# Generated by innovus_enablement/scripts/gen_fakeram.py: abstract 64x124 SRAM.
# Geometry is an assumption (see script header), not PDK data.
VERSION 5.8 ;
BUSBITCHARS "[]" ;
DIVIDERCHAR "/" ;

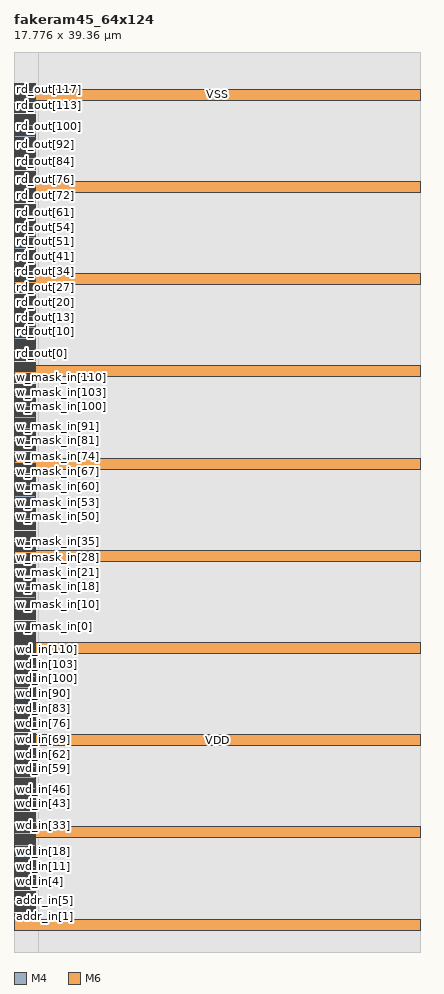
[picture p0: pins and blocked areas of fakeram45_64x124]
MACRO fakeram45_64x124
  CLASS BLOCK ;
  FOREIGN fakeram45_64x124 0 0 ;
  ORIGIN 0 0 ;
  SIZE 17.7760 BY 39.3600 ;
  SYMMETRY X Y R90 ;
  PIN clk
    DIRECTION INPUT ;
    USE CLOCK ;
    PORT
      LAYER M4 ;
        RECT 0 1.4640 0.9600 1.5120 ;
    END
  END clk
  PIN ce_in
    DIRECTION INPUT ;
    USE SIGNAL ;
    PORT
      LAYER M4 ;
        RECT 0 1.5600 0.9600 1.6080 ;
    END
  END ce_in
  PIN we_in
    DIRECTION INPUT ;
    USE SIGNAL ;
    PORT
      LAYER M4 ;
        RECT 0 1.6560 0.9600 1.7040 ;
    END
  END we_in
  PIN addr_in[0]
    DIRECTION INPUT ;
    USE SIGNAL ;
    PORT
      LAYER M4 ;
        RECT 0 1.7520 0.9600 1.8000 ;
    END
  END addr_in[0]
  PIN addr_in[1]
    DIRECTION INPUT ;
    USE SIGNAL ;
    PORT
      LAYER M4 ;
        RECT 0 1.8480 0.9600 1.8960 ;
    END
  END addr_in[1]
  PIN addr_in[2]
    DIRECTION INPUT ;
    USE SIGNAL ;
    PORT
      LAYER M4 ;
        RECT 0 1.9440 0.9600 1.9920 ;
    END
  END addr_in[2]
  PIN addr_in[3]
    DIRECTION INPUT ;
    USE SIGNAL ;
    PORT
      LAYER M4 ;
        RECT 0 2.0400 0.9600 2.0880 ;
    END
  END addr_in[3]
  PIN addr_in[4]
    DIRECTION INPUT ;
    USE SIGNAL ;
    PORT
      LAYER M4 ;
        RECT 0 2.1360 0.9600 2.1840 ;
    END
  END addr_in[4]
  PIN addr_in[5]
    DIRECTION INPUT ;
    USE SIGNAL ;
    PORT
      LAYER M4 ;
        RECT 0 2.2320 0.9600 2.2800 ;
    END
  END addr_in[5]
  PIN wd_in[0]
    DIRECTION INPUT ;
    USE SIGNAL ;
    PORT
      LAYER M4 ;
        RECT 0 2.3280 0.9600 2.3760 ;
    END
  END wd_in[0]
  PIN wd_in[1]
    DIRECTION INPUT ;
    USE SIGNAL ;
    PORT
      LAYER M4 ;
        RECT 0 2.4240 0.9600 2.4720 ;
    END
  END wd_in[1]
  PIN wd_in[2]
    DIRECTION INPUT ;
    USE SIGNAL ;
    PORT
      LAYER M4 ;
        RECT 0 2.5200 0.9600 2.5680 ;
    END
  END wd_in[2]
  PIN wd_in[3]
    DIRECTION INPUT ;
    USE SIGNAL ;
    PORT
      LAYER M4 ;
        RECT 0 2.6160 0.9600 2.6640 ;
    END
  END wd_in[3]
  PIN wd_in[4]
    DIRECTION INPUT ;
    USE SIGNAL ;
    PORT
      LAYER M4 ;
        RECT 0 2.7120 0.9600 2.7600 ;
    END
  END wd_in[4]
  PIN wd_in[5]
    DIRECTION INPUT ;
    USE SIGNAL ;
    PORT
      LAYER M4 ;
        RECT 0 2.8080 0.9600 2.8560 ;
    END
  END wd_in[5]
  PIN wd_in[6]
    DIRECTION INPUT ;
    USE SIGNAL ;
    PORT
      LAYER M4 ;
        RECT 0 2.9040 0.9600 2.9520 ;
    END
  END wd_in[6]
  PIN wd_in[7]
    DIRECTION INPUT ;
    USE SIGNAL ;
    PORT
      LAYER M4 ;
        RECT 0 3.0000 0.9600 3.0480 ;
    END
  END wd_in[7]
  PIN wd_in[8]
    DIRECTION INPUT ;
    USE SIGNAL ;
    PORT
      LAYER M4 ;
        RECT 0 3.0960 0.9600 3.1440 ;
    END
  END wd_in[8]
  PIN wd_in[9]
    DIRECTION INPUT ;
    USE SIGNAL ;
    PORT
      LAYER M4 ;
        RECT 0 3.1920 0.9600 3.2400 ;
    END
  END wd_in[9]
  PIN wd_in[10]
    DIRECTION INPUT ;
    USE SIGNAL ;
    PORT
      LAYER M4 ;
        RECT 0 3.2880 0.9600 3.3360 ;
    END
  END wd_in[10]
  PIN wd_in[11]
    DIRECTION INPUT ;
    USE SIGNAL ;
    PORT
      LAYER M4 ;
        RECT 0 3.3840 0.9600 3.4320 ;
    END
  END wd_in[11]
  PIN wd_in[12]
    DIRECTION INPUT ;
    USE SIGNAL ;
    PORT
      LAYER M4 ;
        RECT 0 3.4800 0.9600 3.5280 ;
    END
  END wd_in[12]
  PIN wd_in[13]
    DIRECTION INPUT ;
    USE SIGNAL ;
    PORT
      LAYER M4 ;
        RECT 0 3.5760 0.9600 3.6240 ;
    END
  END wd_in[13]
  PIN wd_in[14]
    DIRECTION INPUT ;
    USE SIGNAL ;
    PORT
      LAYER M4 ;
        RECT 0 3.6720 0.9600 3.7200 ;
    END
  END wd_in[14]
  PIN wd_in[15]
    DIRECTION INPUT ;
    USE SIGNAL ;
    PORT
      LAYER M4 ;
        RECT 0 3.7680 0.9600 3.8160 ;
    END
  END wd_in[15]
  PIN wd_in[16]
    DIRECTION INPUT ;
    USE SIGNAL ;
    PORT
      LAYER M4 ;
        RECT 0 3.8640 0.9600 3.9120 ;
    END
  END wd_in[16]
  PIN wd_in[17]
    DIRECTION INPUT ;
    USE SIGNAL ;
    PORT
      LAYER M4 ;
        RECT 0 3.9600 0.9600 4.0080 ;
    END
  END wd_in[17]
  PIN wd_in[18]
    DIRECTION INPUT ;
    USE SIGNAL ;
    PORT
      LAYER M4 ;
        RECT 0 4.0560 0.9600 4.1040 ;
    END
  END wd_in[18]
  PIN wd_in[19]
    DIRECTION INPUT ;
    USE SIGNAL ;
    PORT
      LAYER M4 ;
        RECT 0 4.1520 0.9600 4.2000 ;
    END
  END wd_in[19]
  PIN wd_in[20]
    DIRECTION INPUT ;
    USE SIGNAL ;
    PORT
      LAYER M4 ;
        RECT 0 4.2480 0.9600 4.2960 ;
    END
  END wd_in[20]
  PIN wd_in[21]
    DIRECTION INPUT ;
    USE SIGNAL ;
    PORT
      LAYER M4 ;
        RECT 0 4.3440 0.9600 4.3920 ;
    END
  END wd_in[21]
  PIN wd_in[22]
    DIRECTION INPUT ;
    USE SIGNAL ;
    PORT
      LAYER M4 ;
        RECT 0 4.4400 0.9600 4.4880 ;
    END
  END wd_in[22]
  PIN wd_in[23]
    DIRECTION INPUT ;
    USE SIGNAL ;
    PORT
      LAYER M4 ;
        RECT 0 4.5360 0.9600 4.5840 ;
    END
  END wd_in[23]
  PIN wd_in[24]
    DIRECTION INPUT ;
    USE SIGNAL ;
    PORT
      LAYER M4 ;
        RECT 0 4.6320 0.9600 4.6800 ;
    END
  END wd_in[24]
  PIN wd_in[25]
    DIRECTION INPUT ;
    USE SIGNAL ;
    PORT
      LAYER M4 ;
        RECT 0 4.7280 0.9600 4.7760 ;
    END
  END wd_in[25]
  PIN wd_in[26]
    DIRECTION INPUT ;
    USE SIGNAL ;
    PORT
      LAYER M4 ;
        RECT 0 4.8240 0.9600 4.8720 ;
    END
  END wd_in[26]
  PIN wd_in[27]
    DIRECTION INPUT ;
    USE SIGNAL ;
    PORT
      LAYER M4 ;
        RECT 0 4.9200 0.9600 4.9680 ;
    END
  END wd_in[27]
  PIN wd_in[28]
    DIRECTION INPUT ;
    USE SIGNAL ;
    PORT
      LAYER M4 ;
        RECT 0 5.0160 0.9600 5.0640 ;
    END
  END wd_in[28]
  PIN wd_in[29]
    DIRECTION INPUT ;
    USE SIGNAL ;
    PORT
      LAYER M4 ;
        RECT 0 5.1120 0.9600 5.1600 ;
    END
  END wd_in[29]
  PIN wd_in[30]
    DIRECTION INPUT ;
    USE SIGNAL ;
    PORT
      LAYER M4 ;
        RECT 0 5.2080 0.9600 5.2560 ;
    END
  END wd_in[30]
  PIN wd_in[31]
    DIRECTION INPUT ;
    USE SIGNAL ;
    PORT
      LAYER M4 ;
        RECT 0 5.3040 0.9600 5.3520 ;
    END
  END wd_in[31]
  PIN wd_in[32]
    DIRECTION INPUT ;
    USE SIGNAL ;
    PORT
      LAYER M4 ;
        RECT 0 5.4000 0.9600 5.4480 ;
    END
  END wd_in[32]
  PIN wd_in[33]
    DIRECTION INPUT ;
    USE SIGNAL ;
    PORT
      LAYER M4 ;
        RECT 0 5.4960 0.9600 5.5440 ;
    END
  END wd_in[33]
  PIN wd_in[34]
    DIRECTION INPUT ;
    USE SIGNAL ;
    PORT
      LAYER M4 ;
        RECT 0 5.5920 0.9600 5.6400 ;
    END
  END wd_in[34]
  PIN wd_in[35]
    DIRECTION INPUT ;
    USE SIGNAL ;
    PORT
      LAYER M4 ;
        RECT 0 5.6880 0.9600 5.7360 ;
    END
  END wd_in[35]
  PIN wd_in[36]
    DIRECTION INPUT ;
    USE SIGNAL ;
    PORT
      LAYER M4 ;
        RECT 0 5.7840 0.9600 5.8320 ;
    END
  END wd_in[36]
  PIN wd_in[37]
    DIRECTION INPUT ;
    USE SIGNAL ;
    PORT
      LAYER M4 ;
        RECT 0 5.8800 0.9600 5.9280 ;
    END
  END wd_in[37]
  PIN wd_in[38]
    DIRECTION INPUT ;
    USE SIGNAL ;
    PORT
      LAYER M4 ;
        RECT 0 5.9760 0.9600 6.0240 ;
    END
  END wd_in[38]
  PIN wd_in[39]
    DIRECTION INPUT ;
    USE SIGNAL ;
    PORT
      LAYER M4 ;
        RECT 0 6.0720 0.9600 6.1200 ;
    END
  END wd_in[39]
  PIN wd_in[40]
    DIRECTION INPUT ;
    USE SIGNAL ;
    PORT
      LAYER M4 ;
        RECT 0 6.1680 0.9600 6.2160 ;
    END
  END wd_in[40]
  PIN wd_in[41]
    DIRECTION INPUT ;
    USE SIGNAL ;
    PORT
      LAYER M4 ;
        RECT 0 6.2640 0.9600 6.3120 ;
    END
  END wd_in[41]
  PIN wd_in[42]
    DIRECTION INPUT ;
    USE SIGNAL ;
    PORT
      LAYER M4 ;
        RECT 0 6.3600 0.9600 6.4080 ;
    END
  END wd_in[42]
  PIN wd_in[43]
    DIRECTION INPUT ;
    USE SIGNAL ;
    PORT
      LAYER M4 ;
        RECT 0 6.4560 0.9600 6.5040 ;
    END
  END wd_in[43]
  PIN wd_in[44]
    DIRECTION INPUT ;
    USE SIGNAL ;
    PORT
      LAYER M4 ;
        RECT 0 6.5520 0.9600 6.6000 ;
    END
  END wd_in[44]
  PIN wd_in[45]
    DIRECTION INPUT ;
    USE SIGNAL ;
    PORT
      LAYER M4 ;
        RECT 0 6.6480 0.9600 6.6960 ;
    END
  END wd_in[45]
  PIN wd_in[46]
    DIRECTION INPUT ;
    USE SIGNAL ;
    PORT
      LAYER M4 ;
        RECT 0 6.7440 0.9600 6.7920 ;
    END
  END wd_in[46]
  PIN wd_in[47]
    DIRECTION INPUT ;
    USE SIGNAL ;
    PORT
      LAYER M4 ;
        RECT 0 6.8400 0.9600 6.8880 ;
    END
  END wd_in[47]
  PIN wd_in[48]
    DIRECTION INPUT ;
    USE SIGNAL ;
    PORT
      LAYER M4 ;
        RECT 0 6.9360 0.9600 6.9840 ;
    END
  END wd_in[48]
  PIN wd_in[49]
    DIRECTION INPUT ;
    USE SIGNAL ;
    PORT
      LAYER M4 ;
        RECT 0 7.0320 0.9600 7.0800 ;
    END
  END wd_in[49]
  PIN wd_in[50]
    DIRECTION INPUT ;
    USE SIGNAL ;
    PORT
      LAYER M4 ;
        RECT 0 7.1280 0.9600 7.1760 ;
    END
  END wd_in[50]
  PIN wd_in[51]
    DIRECTION INPUT ;
    USE SIGNAL ;
    PORT
      LAYER M4 ;
        RECT 0 7.2240 0.9600 7.2720 ;
    END
  END wd_in[51]
  PIN wd_in[52]
    DIRECTION INPUT ;
    USE SIGNAL ;
    PORT
      LAYER M4 ;
        RECT 0 7.3200 0.9600 7.3680 ;
    END
  END wd_in[52]
  PIN wd_in[53]
    DIRECTION INPUT ;
    USE SIGNAL ;
    PORT
      LAYER M4 ;
        RECT 0 7.4160 0.9600 7.4640 ;
    END
  END wd_in[53]
  PIN wd_in[54]
    DIRECTION INPUT ;
    USE SIGNAL ;
    PORT
      LAYER M4 ;
        RECT 0 7.5120 0.9600 7.5600 ;
    END
  END wd_in[54]
  PIN wd_in[55]
    DIRECTION INPUT ;
    USE SIGNAL ;
    PORT
      LAYER M4 ;
        RECT 0 7.6080 0.9600 7.6560 ;
    END
  END wd_in[55]
  PIN wd_in[56]
    DIRECTION INPUT ;
    USE SIGNAL ;
    PORT
      LAYER M4 ;
        RECT 0 7.7040 0.9600 7.7520 ;
    END
  END wd_in[56]
  PIN wd_in[57]
    DIRECTION INPUT ;
    USE SIGNAL ;
    PORT
      LAYER M4 ;
        RECT 0 7.8000 0.9600 7.8480 ;
    END
  END wd_in[57]
  PIN wd_in[58]
    DIRECTION INPUT ;
    USE SIGNAL ;
    PORT
      LAYER M4 ;
        RECT 0 7.8960 0.9600 7.9440 ;
    END
  END wd_in[58]
  PIN wd_in[59]
    DIRECTION INPUT ;
    USE SIGNAL ;
    PORT
      LAYER M4 ;
        RECT 0 7.9920 0.9600 8.0400 ;
    END
  END wd_in[59]
  PIN wd_in[60]
    DIRECTION INPUT ;
    USE SIGNAL ;
    PORT
      LAYER M4 ;
        RECT 0 8.0880 0.9600 8.1360 ;
    END
  END wd_in[60]
  PIN wd_in[61]
    DIRECTION INPUT ;
    USE SIGNAL ;
    PORT
      LAYER M4 ;
        RECT 0 8.1840 0.9600 8.2320 ;
    END
  END wd_in[61]
  PIN wd_in[62]
    DIRECTION INPUT ;
    USE SIGNAL ;
    PORT
      LAYER M4 ;
        RECT 0 8.2800 0.9600 8.3280 ;
    END
  END wd_in[62]
  PIN wd_in[63]
    DIRECTION INPUT ;
    USE SIGNAL ;
    PORT
      LAYER M4 ;
        RECT 0 8.3760 0.9600 8.4240 ;
    END
  END wd_in[63]
  PIN wd_in[64]
    DIRECTION INPUT ;
    USE SIGNAL ;
    PORT
      LAYER M4 ;
        RECT 0 8.4720 0.9600 8.5200 ;
    END
  END wd_in[64]
  PIN wd_in[65]
    DIRECTION INPUT ;
    USE SIGNAL ;
    PORT
      LAYER M4 ;
        RECT 0 8.5680 0.9600 8.6160 ;
    END
  END wd_in[65]
  PIN wd_in[66]
    DIRECTION INPUT ;
    USE SIGNAL ;
    PORT
      LAYER M4 ;
        RECT 0 8.6640 0.9600 8.7120 ;
    END
  END wd_in[66]
  PIN wd_in[67]
    DIRECTION INPUT ;
    USE SIGNAL ;
    PORT
      LAYER M4 ;
        RECT 0 8.7600 0.9600 8.8080 ;
    END
  END wd_in[67]
  PIN wd_in[68]
    DIRECTION INPUT ;
    USE SIGNAL ;
    PORT
      LAYER M4 ;
        RECT 0 8.8560 0.9600 8.9040 ;
    END
  END wd_in[68]
  PIN wd_in[69]
    DIRECTION INPUT ;
    USE SIGNAL ;
    PORT
      LAYER M4 ;
        RECT 0 8.9520 0.9600 9.0000 ;
    END
  END wd_in[69]
  PIN wd_in[70]
    DIRECTION INPUT ;
    USE SIGNAL ;
    PORT
      LAYER M4 ;
        RECT 0 9.0480 0.9600 9.0960 ;
    END
  END wd_in[70]
  PIN wd_in[71]
    DIRECTION INPUT ;
    USE SIGNAL ;
    PORT
      LAYER M4 ;
        RECT 0 9.1440 0.9600 9.1920 ;
    END
  END wd_in[71]
  PIN wd_in[72]
    DIRECTION INPUT ;
    USE SIGNAL ;
    PORT
      LAYER M4 ;
        RECT 0 9.2400 0.9600 9.2880 ;
    END
  END wd_in[72]
  PIN wd_in[73]
    DIRECTION INPUT ;
    USE SIGNAL ;
    PORT
      LAYER M4 ;
        RECT 0 9.3360 0.9600 9.3840 ;
    END
  END wd_in[73]
  PIN wd_in[74]
    DIRECTION INPUT ;
    USE SIGNAL ;
    PORT
      LAYER M4 ;
        RECT 0 9.4320 0.9600 9.4800 ;
    END
  END wd_in[74]
  PIN wd_in[75]
    DIRECTION INPUT ;
    USE SIGNAL ;
    PORT
      LAYER M4 ;
        RECT 0 9.5280 0.9600 9.5760 ;
    END
  END wd_in[75]
  PIN wd_in[76]
    DIRECTION INPUT ;
    USE SIGNAL ;
    PORT
      LAYER M4 ;
        RECT 0 9.6240 0.9600 9.6720 ;
    END
  END wd_in[76]
  PIN wd_in[77]
    DIRECTION INPUT ;
    USE SIGNAL ;
    PORT
      LAYER M4 ;
        RECT 0 9.7200 0.9600 9.7680 ;
    END
  END wd_in[77]
  PIN wd_in[78]
    DIRECTION INPUT ;
    USE SIGNAL ;
    PORT
      LAYER M4 ;
        RECT 0 9.8160 0.9600 9.8640 ;
    END
  END wd_in[78]
  PIN wd_in[79]
    DIRECTION INPUT ;
    USE SIGNAL ;
    PORT
      LAYER M4 ;
        RECT 0 9.9120 0.9600 9.9600 ;
    END
  END wd_in[79]
  PIN wd_in[80]
    DIRECTION INPUT ;
    USE SIGNAL ;
    PORT
      LAYER M4 ;
        RECT 0 10.0080 0.9600 10.0560 ;
    END
  END wd_in[80]
  PIN wd_in[81]
    DIRECTION INPUT ;
    USE SIGNAL ;
    PORT
      LAYER M4 ;
        RECT 0 10.1040 0.9600 10.1520 ;
    END
  END wd_in[81]
  PIN wd_in[82]
    DIRECTION INPUT ;
    USE SIGNAL ;
    PORT
      LAYER M4 ;
        RECT 0 10.2000 0.9600 10.2480 ;
    END
  END wd_in[82]
  PIN wd_in[83]
    DIRECTION INPUT ;
    USE SIGNAL ;
    PORT
      LAYER M4 ;
        RECT 0 10.2960 0.9600 10.3440 ;
    END
  END wd_in[83]
  PIN wd_in[84]
    DIRECTION INPUT ;
    USE SIGNAL ;
    PORT
      LAYER M4 ;
        RECT 0 10.3920 0.9600 10.4400 ;
    END
  END wd_in[84]
  PIN wd_in[85]
    DIRECTION INPUT ;
    USE SIGNAL ;
    PORT
      LAYER M4 ;
        RECT 0 10.4880 0.9600 10.5360 ;
    END
  END wd_in[85]
  PIN wd_in[86]
    DIRECTION INPUT ;
    USE SIGNAL ;
    PORT
      LAYER M4 ;
        RECT 0 10.5840 0.9600 10.6320 ;
    END
  END wd_in[86]
  PIN wd_in[87]
    DIRECTION INPUT ;
    USE SIGNAL ;
    PORT
      LAYER M4 ;
        RECT 0 10.6800 0.9600 10.7280 ;
    END
  END wd_in[87]
  PIN wd_in[88]
    DIRECTION INPUT ;
    USE SIGNAL ;
    PORT
      LAYER M4 ;
        RECT 0 10.7760 0.9600 10.8240 ;
    END
  END wd_in[88]
  PIN wd_in[89]
    DIRECTION INPUT ;
    USE SIGNAL ;
    PORT
      LAYER M4 ;
        RECT 0 10.8720 0.9600 10.9200 ;
    END
  END wd_in[89]
  PIN wd_in[90]
    DIRECTION INPUT ;
    USE SIGNAL ;
    PORT
      LAYER M4 ;
        RECT 0 10.9680 0.9600 11.0160 ;
    END
  END wd_in[90]
  PIN wd_in[91]
    DIRECTION INPUT ;
    USE SIGNAL ;
    PORT
      LAYER M4 ;
        RECT 0 11.0640 0.9600 11.1120 ;
    END
  END wd_in[91]
  PIN wd_in[92]
    DIRECTION INPUT ;
    USE SIGNAL ;
    PORT
      LAYER M4 ;
        RECT 0 11.1600 0.9600 11.2080 ;
    END
  END wd_in[92]
  PIN wd_in[93]
    DIRECTION INPUT ;
    USE SIGNAL ;
    PORT
      LAYER M4 ;
        RECT 0 11.2560 0.9600 11.3040 ;
    END
  END wd_in[93]
  PIN wd_in[94]
    DIRECTION INPUT ;
    USE SIGNAL ;
    PORT
      LAYER M4 ;
        RECT 0 11.3520 0.9600 11.4000 ;
    END
  END wd_in[94]
  PIN wd_in[95]
    DIRECTION INPUT ;
    USE SIGNAL ;
    PORT
      LAYER M4 ;
        RECT 0 11.4480 0.9600 11.4960 ;
    END
  END wd_in[95]
  PIN wd_in[96]
    DIRECTION INPUT ;
    USE SIGNAL ;
    PORT
      LAYER M4 ;
        RECT 0 11.5440 0.9600 11.5920 ;
    END
  END wd_in[96]
  PIN wd_in[97]
    DIRECTION INPUT ;
    USE SIGNAL ;
    PORT
      LAYER M4 ;
        RECT 0 11.6400 0.9600 11.6880 ;
    END
  END wd_in[97]
  PIN wd_in[98]
    DIRECTION INPUT ;
    USE SIGNAL ;
    PORT
      LAYER M4 ;
        RECT 0 11.7360 0.9600 11.7840 ;
    END
  END wd_in[98]
  PIN wd_in[99]
    DIRECTION INPUT ;
    USE SIGNAL ;
    PORT
      LAYER M4 ;
        RECT 0 11.8320 0.9600 11.8800 ;
    END
  END wd_in[99]
  PIN wd_in[100]
    DIRECTION INPUT ;
    USE SIGNAL ;
    PORT
      LAYER M4 ;
        RECT 0 11.9280 0.9600 11.9760 ;
    END
  END wd_in[100]
  PIN wd_in[101]
    DIRECTION INPUT ;
    USE SIGNAL ;
    PORT
      LAYER M4 ;
        RECT 0 12.0240 0.9600 12.0720 ;
    END
  END wd_in[101]
  PIN wd_in[102]
    DIRECTION INPUT ;
    USE SIGNAL ;
    PORT
      LAYER M4 ;
        RECT 0 12.1200 0.9600 12.1680 ;
    END
  END wd_in[102]
  PIN wd_in[103]
    DIRECTION INPUT ;
    USE SIGNAL ;
    PORT
      LAYER M4 ;
        RECT 0 12.2160 0.9600 12.2640 ;
    END
  END wd_in[103]
  PIN wd_in[104]
    DIRECTION INPUT ;
    USE SIGNAL ;
    PORT
      LAYER M4 ;
        RECT 0 12.3120 0.9600 12.3600 ;
    END
  END wd_in[104]
  PIN wd_in[105]
    DIRECTION INPUT ;
    USE SIGNAL ;
    PORT
      LAYER M4 ;
        RECT 0 12.4080 0.9600 12.4560 ;
    END
  END wd_in[105]
  PIN wd_in[106]
    DIRECTION INPUT ;
    USE SIGNAL ;
    PORT
      LAYER M4 ;
        RECT 0 12.5040 0.9600 12.5520 ;
    END
  END wd_in[106]
  PIN wd_in[107]
    DIRECTION INPUT ;
    USE SIGNAL ;
    PORT
      LAYER M4 ;
        RECT 0 12.6000 0.9600 12.6480 ;
    END
  END wd_in[107]
  PIN wd_in[108]
    DIRECTION INPUT ;
    USE SIGNAL ;
    PORT
      LAYER M4 ;
        RECT 0 12.6960 0.9600 12.7440 ;
    END
  END wd_in[108]
  PIN wd_in[109]
    DIRECTION INPUT ;
    USE SIGNAL ;
    PORT
      LAYER M4 ;
        RECT 0 12.7920 0.9600 12.8400 ;
    END
  END wd_in[109]
  PIN wd_in[110]
    DIRECTION INPUT ;
    USE SIGNAL ;
    PORT
      LAYER M4 ;
        RECT 0 12.8880 0.9600 12.9360 ;
    END
  END wd_in[110]
  PIN wd_in[111]
    DIRECTION INPUT ;
    USE SIGNAL ;
    PORT
      LAYER M4 ;
        RECT 0 12.9840 0.9600 13.0320 ;
    END
  END wd_in[111]
  PIN wd_in[112]
    DIRECTION INPUT ;
    USE SIGNAL ;
    PORT
      LAYER M4 ;
        RECT 0 13.0800 0.9600 13.1280 ;
    END
  END wd_in[112]
  PIN wd_in[113]
    DIRECTION INPUT ;
    USE SIGNAL ;
    PORT
      LAYER M4 ;
        RECT 0 13.1760 0.9600 13.2240 ;
    END
  END wd_in[113]
  PIN wd_in[114]
    DIRECTION INPUT ;
    USE SIGNAL ;
    PORT
      LAYER M4 ;
        RECT 0 13.2720 0.9600 13.3200 ;
    END
  END wd_in[114]
  PIN wd_in[115]
    DIRECTION INPUT ;
    USE SIGNAL ;
    PORT
      LAYER M4 ;
        RECT 0 13.3680 0.9600 13.4160 ;
    END
  END wd_in[115]
  PIN wd_in[116]
    DIRECTION INPUT ;
    USE SIGNAL ;
    PORT
      LAYER M4 ;
        RECT 0 13.4640 0.9600 13.5120 ;
    END
  END wd_in[116]
  PIN wd_in[117]
    DIRECTION INPUT ;
    USE SIGNAL ;
    PORT
      LAYER M4 ;
        RECT 0 13.5600 0.9600 13.6080 ;
    END
  END wd_in[117]
  PIN wd_in[118]
    DIRECTION INPUT ;
    USE SIGNAL ;
    PORT
      LAYER M4 ;
        RECT 0 13.6560 0.9600 13.7040 ;
    END
  END wd_in[118]
  PIN wd_in[119]
    DIRECTION INPUT ;
    USE SIGNAL ;
    PORT
      LAYER M4 ;
        RECT 0 13.7520 0.9600 13.8000 ;
    END
  END wd_in[119]
  PIN wd_in[120]
    DIRECTION INPUT ;
    USE SIGNAL ;
    PORT
      LAYER M4 ;
        RECT 0 13.8480 0.9600 13.8960 ;
    END
  END wd_in[120]
  PIN wd_in[121]
    DIRECTION INPUT ;
    USE SIGNAL ;
    PORT
      LAYER M4 ;
        RECT 0 13.9440 0.9600 13.9920 ;
    END
  END wd_in[121]
  PIN wd_in[122]
    DIRECTION INPUT ;
    USE SIGNAL ;
    PORT
      LAYER M4 ;
        RECT 0 14.0400 0.9600 14.0880 ;
    END
  END wd_in[122]
  PIN wd_in[123]
    DIRECTION INPUT ;
    USE SIGNAL ;
    PORT
      LAYER M4 ;
        RECT 0 14.1360 0.9600 14.1840 ;
    END
  END wd_in[123]
  PIN w_mask_in[0]
    DIRECTION INPUT ;
    USE SIGNAL ;
    PORT
      LAYER M4 ;
        RECT 0 14.2320 0.9600 14.2800 ;
    END
  END w_mask_in[0]
  PIN w_mask_in[1]
    DIRECTION INPUT ;
    USE SIGNAL ;
    PORT
      LAYER M4 ;
        RECT 0 14.3280 0.9600 14.3760 ;
    END
  END w_mask_in[1]
  PIN w_mask_in[2]
    DIRECTION INPUT ;
    USE SIGNAL ;
    PORT
      LAYER M4 ;
        RECT 0 14.4240 0.9600 14.4720 ;
    END
  END w_mask_in[2]
  PIN w_mask_in[3]
    DIRECTION INPUT ;
    USE SIGNAL ;
    PORT
      LAYER M4 ;
        RECT 0 14.5200 0.9600 14.5680 ;
    END
  END w_mask_in[3]
  PIN w_mask_in[4]
    DIRECTION INPUT ;
    USE SIGNAL ;
    PORT
      LAYER M4 ;
        RECT 0 14.6160 0.9600 14.6640 ;
    END
  END w_mask_in[4]
  PIN w_mask_in[5]
    DIRECTION INPUT ;
    USE SIGNAL ;
    PORT
      LAYER M4 ;
        RECT 0 14.7120 0.9600 14.7600 ;
    END
  END w_mask_in[5]
  PIN w_mask_in[6]
    DIRECTION INPUT ;
    USE SIGNAL ;
    PORT
      LAYER M4 ;
        RECT 0 14.8080 0.9600 14.8560 ;
    END
  END w_mask_in[6]
  PIN w_mask_in[7]
    DIRECTION INPUT ;
    USE SIGNAL ;
    PORT
      LAYER M4 ;
        RECT 0 14.9040 0.9600 14.9520 ;
    END
  END w_mask_in[7]
  PIN w_mask_in[8]
    DIRECTION INPUT ;
    USE SIGNAL ;
    PORT
      LAYER M4 ;
        RECT 0 15.0000 0.9600 15.0480 ;
    END
  END w_mask_in[8]
  PIN w_mask_in[9]
    DIRECTION INPUT ;
    USE SIGNAL ;
    PORT
      LAYER M4 ;
        RECT 0 15.0960 0.9600 15.1440 ;
    END
  END w_mask_in[9]
  PIN w_mask_in[10]
    DIRECTION INPUT ;
    USE SIGNAL ;
    PORT
      LAYER M4 ;
        RECT 0 15.1920 0.9600 15.2400 ;
    END
  END w_mask_in[10]
  PIN w_mask_in[11]
    DIRECTION INPUT ;
    USE SIGNAL ;
    PORT
      LAYER M4 ;
        RECT 0 15.2880 0.9600 15.3360 ;
    END
  END w_mask_in[11]
  PIN w_mask_in[12]
    DIRECTION INPUT ;
    USE SIGNAL ;
    PORT
      LAYER M4 ;
        RECT 0 15.3840 0.9600 15.4320 ;
    END
  END w_mask_in[12]
  PIN w_mask_in[13]
    DIRECTION INPUT ;
    USE SIGNAL ;
    PORT
      LAYER M4 ;
        RECT 0 15.4800 0.9600 15.5280 ;
    END
  END w_mask_in[13]
  PIN w_mask_in[14]
    DIRECTION INPUT ;
    USE SIGNAL ;
    PORT
      LAYER M4 ;
        RECT 0 15.5760 0.9600 15.6240 ;
    END
  END w_mask_in[14]
  PIN w_mask_in[15]
    DIRECTION INPUT ;
    USE SIGNAL ;
    PORT
      LAYER M4 ;
        RECT 0 15.6720 0.9600 15.7200 ;
    END
  END w_mask_in[15]
  PIN w_mask_in[16]
    DIRECTION INPUT ;
    USE SIGNAL ;
    PORT
      LAYER M4 ;
        RECT 0 15.7680 0.9600 15.8160 ;
    END
  END w_mask_in[16]
  PIN w_mask_in[17]
    DIRECTION INPUT ;
    USE SIGNAL ;
    PORT
      LAYER M4 ;
        RECT 0 15.8640 0.9600 15.9120 ;
    END
  END w_mask_in[17]
  PIN w_mask_in[18]
    DIRECTION INPUT ;
    USE SIGNAL ;
    PORT
      LAYER M4 ;
        RECT 0 15.9600 0.9600 16.0080 ;
    END
  END w_mask_in[18]
  PIN w_mask_in[19]
    DIRECTION INPUT ;
    USE SIGNAL ;
    PORT
      LAYER M4 ;
        RECT 0 16.0560 0.9600 16.1040 ;
    END
  END w_mask_in[19]
  PIN w_mask_in[20]
    DIRECTION INPUT ;
    USE SIGNAL ;
    PORT
      LAYER M4 ;
        RECT 0 16.1520 0.9600 16.2000 ;
    END
  END w_mask_in[20]
  PIN w_mask_in[21]
    DIRECTION INPUT ;
    USE SIGNAL ;
    PORT
      LAYER M4 ;
        RECT 0 16.2480 0.9600 16.2960 ;
    END
  END w_mask_in[21]
  PIN w_mask_in[22]
    DIRECTION INPUT ;
    USE SIGNAL ;
    PORT
      LAYER M4 ;
        RECT 0 16.3440 0.9600 16.3920 ;
    END
  END w_mask_in[22]
  PIN w_mask_in[23]
    DIRECTION INPUT ;
    USE SIGNAL ;
    PORT
      LAYER M4 ;
        RECT 0 16.4400 0.9600 16.4880 ;
    END
  END w_mask_in[23]
  PIN w_mask_in[24]
    DIRECTION INPUT ;
    USE SIGNAL ;
    PORT
      LAYER M4 ;
        RECT 0 16.5360 0.9600 16.5840 ;
    END
  END w_mask_in[24]
  PIN w_mask_in[25]
    DIRECTION INPUT ;
    USE SIGNAL ;
    PORT
      LAYER M4 ;
        RECT 0 16.6320 0.9600 16.6800 ;
    END
  END w_mask_in[25]
  PIN w_mask_in[26]
    DIRECTION INPUT ;
    USE SIGNAL ;
    PORT
      LAYER M4 ;
        RECT 0 16.7280 0.9600 16.7760 ;
    END
  END w_mask_in[26]
  PIN w_mask_in[27]
    DIRECTION INPUT ;
    USE SIGNAL ;
    PORT
      LAYER M4 ;
        RECT 0 16.8240 0.9600 16.8720 ;
    END
  END w_mask_in[27]
  PIN w_mask_in[28]
    DIRECTION INPUT ;
    USE SIGNAL ;
    PORT
      LAYER M4 ;
        RECT 0 16.9200 0.9600 16.9680 ;
    END
  END w_mask_in[28]
  PIN w_mask_in[29]
    DIRECTION INPUT ;
    USE SIGNAL ;
    PORT
      LAYER M4 ;
        RECT 0 17.0160 0.9600 17.0640 ;
    END
  END w_mask_in[29]
  PIN w_mask_in[30]
    DIRECTION INPUT ;
    USE SIGNAL ;
    PORT
      LAYER M4 ;
        RECT 0 17.1120 0.9600 17.1600 ;
    END
  END w_mask_in[30]
  PIN w_mask_in[31]
    DIRECTION INPUT ;
    USE SIGNAL ;
    PORT
      LAYER M4 ;
        RECT 0 17.2080 0.9600 17.2560 ;
    END
  END w_mask_in[31]
  PIN w_mask_in[32]
    DIRECTION INPUT ;
    USE SIGNAL ;
    PORT
      LAYER M4 ;
        RECT 0 17.3040 0.9600 17.3520 ;
    END
  END w_mask_in[32]
  PIN w_mask_in[33]
    DIRECTION INPUT ;
    USE SIGNAL ;
    PORT
      LAYER M4 ;
        RECT 0 17.4000 0.9600 17.4480 ;
    END
  END w_mask_in[33]
  PIN w_mask_in[34]
    DIRECTION INPUT ;
    USE SIGNAL ;
    PORT
      LAYER M4 ;
        RECT 0 17.4960 0.9600 17.5440 ;
    END
  END w_mask_in[34]
  PIN w_mask_in[35]
    DIRECTION INPUT ;
    USE SIGNAL ;
    PORT
      LAYER M4 ;
        RECT 0 17.5920 0.9600 17.6400 ;
    END
  END w_mask_in[35]
  PIN w_mask_in[36]
    DIRECTION INPUT ;
    USE SIGNAL ;
    PORT
      LAYER M4 ;
        RECT 0 17.6880 0.9600 17.7360 ;
    END
  END w_mask_in[36]
  PIN w_mask_in[37]
    DIRECTION INPUT ;
    USE SIGNAL ;
    PORT
      LAYER M4 ;
        RECT 0 17.7840 0.9600 17.8320 ;
    END
  END w_mask_in[37]
  PIN w_mask_in[38]
    DIRECTION INPUT ;
    USE SIGNAL ;
    PORT
      LAYER M4 ;
        RECT 0 17.8800 0.9600 17.9280 ;
    END
  END w_mask_in[38]
  PIN w_mask_in[39]
    DIRECTION INPUT ;
    USE SIGNAL ;
    PORT
      LAYER M4 ;
        RECT 0 17.9760 0.9600 18.0240 ;
    END
  END w_mask_in[39]
  PIN w_mask_in[40]
    DIRECTION INPUT ;
    USE SIGNAL ;
    PORT
      LAYER M4 ;
        RECT 0 18.0720 0.9600 18.1200 ;
    END
  END w_mask_in[40]
  PIN w_mask_in[41]
    DIRECTION INPUT ;
    USE SIGNAL ;
    PORT
      LAYER M4 ;
        RECT 0 18.1680 0.9600 18.2160 ;
    END
  END w_mask_in[41]
  PIN w_mask_in[42]
    DIRECTION INPUT ;
    USE SIGNAL ;
    PORT
      LAYER M4 ;
        RECT 0 18.2640 0.9600 18.3120 ;
    END
  END w_mask_in[42]
  PIN w_mask_in[43]
    DIRECTION INPUT ;
    USE SIGNAL ;
    PORT
      LAYER M4 ;
        RECT 0 18.3600 0.9600 18.4080 ;
    END
  END w_mask_in[43]
  PIN w_mask_in[44]
    DIRECTION INPUT ;
    USE SIGNAL ;
    PORT
      LAYER M4 ;
        RECT 0 18.4560 0.9600 18.5040 ;
    END
  END w_mask_in[44]
  PIN w_mask_in[45]
    DIRECTION INPUT ;
    USE SIGNAL ;
    PORT
      LAYER M4 ;
        RECT 0 18.5520 0.9600 18.6000 ;
    END
  END w_mask_in[45]
  PIN w_mask_in[46]
    DIRECTION INPUT ;
    USE SIGNAL ;
    PORT
      LAYER M4 ;
        RECT 0 18.6480 0.9600 18.6960 ;
    END
  END w_mask_in[46]
  PIN w_mask_in[47]
    DIRECTION INPUT ;
    USE SIGNAL ;
    PORT
      LAYER M4 ;
        RECT 0 18.7440 0.9600 18.7920 ;
    END
  END w_mask_in[47]
  PIN w_mask_in[48]
    DIRECTION INPUT ;
    USE SIGNAL ;
    PORT
      LAYER M4 ;
        RECT 0 18.8400 0.9600 18.8880 ;
    END
  END w_mask_in[48]
  PIN w_mask_in[49]
    DIRECTION INPUT ;
    USE SIGNAL ;
    PORT
      LAYER M4 ;
        RECT 0 18.9360 0.9600 18.9840 ;
    END
  END w_mask_in[49]
  PIN w_mask_in[50]
    DIRECTION INPUT ;
    USE SIGNAL ;
    PORT
      LAYER M4 ;
        RECT 0 19.0320 0.9600 19.0800 ;
    END
  END w_mask_in[50]
  PIN w_mask_in[51]
    DIRECTION INPUT ;
    USE SIGNAL ;
    PORT
      LAYER M4 ;
        RECT 0 19.1280 0.9600 19.1760 ;
    END
  END w_mask_in[51]
  PIN w_mask_in[52]
    DIRECTION INPUT ;
    USE SIGNAL ;
    PORT
      LAYER M4 ;
        RECT 0 19.2240 0.9600 19.2720 ;
    END
  END w_mask_in[52]
  PIN w_mask_in[53]
    DIRECTION INPUT ;
    USE SIGNAL ;
    PORT
      LAYER M4 ;
        RECT 0 19.3200 0.9600 19.3680 ;
    END
  END w_mask_in[53]
  PIN w_mask_in[54]
    DIRECTION INPUT ;
    USE SIGNAL ;
    PORT
      LAYER M4 ;
        RECT 0 19.4160 0.9600 19.4640 ;
    END
  END w_mask_in[54]
  PIN w_mask_in[55]
    DIRECTION INPUT ;
    USE SIGNAL ;
    PORT
      LAYER M4 ;
        RECT 0 19.5120 0.9600 19.5600 ;
    END
  END w_mask_in[55]
  PIN w_mask_in[56]
    DIRECTION INPUT ;
    USE SIGNAL ;
    PORT
      LAYER M4 ;
        RECT 0 19.6080 0.9600 19.6560 ;
    END
  END w_mask_in[56]
  PIN w_mask_in[57]
    DIRECTION INPUT ;
    USE SIGNAL ;
    PORT
      LAYER M4 ;
        RECT 0 19.7040 0.9600 19.7520 ;
    END
  END w_mask_in[57]
  PIN w_mask_in[58]
    DIRECTION INPUT ;
    USE SIGNAL ;
    PORT
      LAYER M4 ;
        RECT 0 19.8000 0.9600 19.8480 ;
    END
  END w_mask_in[58]
  PIN w_mask_in[59]
    DIRECTION INPUT ;
    USE SIGNAL ;
    PORT
      LAYER M4 ;
        RECT 0 19.8960 0.9600 19.9440 ;
    END
  END w_mask_in[59]
  PIN w_mask_in[60]
    DIRECTION INPUT ;
    USE SIGNAL ;
    PORT
      LAYER M4 ;
        RECT 0 19.9920 0.9600 20.0400 ;
    END
  END w_mask_in[60]
  PIN w_mask_in[61]
    DIRECTION INPUT ;
    USE SIGNAL ;
    PORT
      LAYER M4 ;
        RECT 0 20.0880 0.9600 20.1360 ;
    END
  END w_mask_in[61]
  PIN w_mask_in[62]
    DIRECTION INPUT ;
    USE SIGNAL ;
    PORT
      LAYER M4 ;
        RECT 0 20.1840 0.9600 20.2320 ;
    END
  END w_mask_in[62]
  PIN w_mask_in[63]
    DIRECTION INPUT ;
    USE SIGNAL ;
    PORT
      LAYER M4 ;
        RECT 0 20.2800 0.9600 20.3280 ;
    END
  END w_mask_in[63]
  PIN w_mask_in[64]
    DIRECTION INPUT ;
    USE SIGNAL ;
    PORT
      LAYER M4 ;
        RECT 0 20.3760 0.9600 20.4240 ;
    END
  END w_mask_in[64]
  PIN w_mask_in[65]
    DIRECTION INPUT ;
    USE SIGNAL ;
    PORT
      LAYER M4 ;
        RECT 0 20.4720 0.9600 20.5200 ;
    END
  END w_mask_in[65]
  PIN w_mask_in[66]
    DIRECTION INPUT ;
    USE SIGNAL ;
    PORT
      LAYER M4 ;
        RECT 0 20.5680 0.9600 20.6160 ;
    END
  END w_mask_in[66]
  PIN w_mask_in[67]
    DIRECTION INPUT ;
    USE SIGNAL ;
    PORT
      LAYER M4 ;
        RECT 0 20.6640 0.9600 20.7120 ;
    END
  END w_mask_in[67]
  PIN w_mask_in[68]
    DIRECTION INPUT ;
    USE SIGNAL ;
    PORT
      LAYER M4 ;
        RECT 0 20.7600 0.9600 20.8080 ;
    END
  END w_mask_in[68]
  PIN w_mask_in[69]
    DIRECTION INPUT ;
    USE SIGNAL ;
    PORT
      LAYER M4 ;
        RECT 0 20.8560 0.9600 20.9040 ;
    END
  END w_mask_in[69]
  PIN w_mask_in[70]
    DIRECTION INPUT ;
    USE SIGNAL ;
    PORT
      LAYER M4 ;
        RECT 0 20.9520 0.9600 21.0000 ;
    END
  END w_mask_in[70]
  PIN w_mask_in[71]
    DIRECTION INPUT ;
    USE SIGNAL ;
    PORT
      LAYER M4 ;
        RECT 0 21.0480 0.9600 21.0960 ;
    END
  END w_mask_in[71]
  PIN w_mask_in[72]
    DIRECTION INPUT ;
    USE SIGNAL ;
    PORT
      LAYER M4 ;
        RECT 0 21.1440 0.9600 21.1920 ;
    END
  END w_mask_in[72]
  PIN w_mask_in[73]
    DIRECTION INPUT ;
    USE SIGNAL ;
    PORT
      LAYER M4 ;
        RECT 0 21.2400 0.9600 21.2880 ;
    END
  END w_mask_in[73]
  PIN w_mask_in[74]
    DIRECTION INPUT ;
    USE SIGNAL ;
    PORT
      LAYER M4 ;
        RECT 0 21.3360 0.9600 21.3840 ;
    END
  END w_mask_in[74]
  PIN w_mask_in[75]
    DIRECTION INPUT ;
    USE SIGNAL ;
    PORT
      LAYER M4 ;
        RECT 0 21.4320 0.9600 21.4800 ;
    END
  END w_mask_in[75]
  PIN w_mask_in[76]
    DIRECTION INPUT ;
    USE SIGNAL ;
    PORT
      LAYER M4 ;
        RECT 0 21.5280 0.9600 21.5760 ;
    END
  END w_mask_in[76]
  PIN w_mask_in[77]
    DIRECTION INPUT ;
    USE SIGNAL ;
    PORT
      LAYER M4 ;
        RECT 0 21.6240 0.9600 21.6720 ;
    END
  END w_mask_in[77]
  PIN w_mask_in[78]
    DIRECTION INPUT ;
    USE SIGNAL ;
    PORT
      LAYER M4 ;
        RECT 0 21.7200 0.9600 21.7680 ;
    END
  END w_mask_in[78]
  PIN w_mask_in[79]
    DIRECTION INPUT ;
    USE SIGNAL ;
    PORT
      LAYER M4 ;
        RECT 0 21.8160 0.9600 21.8640 ;
    END
  END w_mask_in[79]
  PIN w_mask_in[80]
    DIRECTION INPUT ;
    USE SIGNAL ;
    PORT
      LAYER M4 ;
        RECT 0 21.9120 0.9600 21.9600 ;
    END
  END w_mask_in[80]
  PIN w_mask_in[81]
    DIRECTION INPUT ;
    USE SIGNAL ;
    PORT
      LAYER M4 ;
        RECT 0 22.0080 0.9600 22.0560 ;
    END
  END w_mask_in[81]
  PIN w_mask_in[82]
    DIRECTION INPUT ;
    USE SIGNAL ;
    PORT
      LAYER M4 ;
        RECT 0 22.1040 0.9600 22.1520 ;
    END
  END w_mask_in[82]
  PIN w_mask_in[83]
    DIRECTION INPUT ;
    USE SIGNAL ;
    PORT
      LAYER M4 ;
        RECT 0 22.2000 0.9600 22.2480 ;
    END
  END w_mask_in[83]
  PIN w_mask_in[84]
    DIRECTION INPUT ;
    USE SIGNAL ;
    PORT
      LAYER M4 ;
        RECT 0 22.2960 0.9600 22.3440 ;
    END
  END w_mask_in[84]
  PIN w_mask_in[85]
    DIRECTION INPUT ;
    USE SIGNAL ;
    PORT
      LAYER M4 ;
        RECT 0 22.3920 0.9600 22.4400 ;
    END
  END w_mask_in[85]
  PIN w_mask_in[86]
    DIRECTION INPUT ;
    USE SIGNAL ;
    PORT
      LAYER M4 ;
        RECT 0 22.4880 0.9600 22.5360 ;
    END
  END w_mask_in[86]
  PIN w_mask_in[87]
    DIRECTION INPUT ;
    USE SIGNAL ;
    PORT
      LAYER M4 ;
        RECT 0 22.5840 0.9600 22.6320 ;
    END
  END w_mask_in[87]
  PIN w_mask_in[88]
    DIRECTION INPUT ;
    USE SIGNAL ;
    PORT
      LAYER M4 ;
        RECT 0 22.6800 0.9600 22.7280 ;
    END
  END w_mask_in[88]
  PIN w_mask_in[89]
    DIRECTION INPUT ;
    USE SIGNAL ;
    PORT
      LAYER M4 ;
        RECT 0 22.7760 0.9600 22.8240 ;
    END
  END w_mask_in[89]
  PIN w_mask_in[90]
    DIRECTION INPUT ;
    USE SIGNAL ;
    PORT
      LAYER M4 ;
        RECT 0 22.8720 0.9600 22.9200 ;
    END
  END w_mask_in[90]
  PIN w_mask_in[91]
    DIRECTION INPUT ;
    USE SIGNAL ;
    PORT
      LAYER M4 ;
        RECT 0 22.9680 0.9600 23.0160 ;
    END
  END w_mask_in[91]
  PIN w_mask_in[92]
    DIRECTION INPUT ;
    USE SIGNAL ;
    PORT
      LAYER M4 ;
        RECT 0 23.0640 0.9600 23.1120 ;
    END
  END w_mask_in[92]
  PIN w_mask_in[93]
    DIRECTION INPUT ;
    USE SIGNAL ;
    PORT
      LAYER M4 ;
        RECT 0 23.1600 0.9600 23.2080 ;
    END
  END w_mask_in[93]
  PIN w_mask_in[94]
    DIRECTION INPUT ;
    USE SIGNAL ;
    PORT
      LAYER M4 ;
        RECT 0 23.2560 0.9600 23.3040 ;
    END
  END w_mask_in[94]
  PIN w_mask_in[95]
    DIRECTION INPUT ;
    USE SIGNAL ;
    PORT
      LAYER M4 ;
        RECT 0 23.3520 0.9600 23.4000 ;
    END
  END w_mask_in[95]
  PIN w_mask_in[96]
    DIRECTION INPUT ;
    USE SIGNAL ;
    PORT
      LAYER M4 ;
        RECT 0 23.4480 0.9600 23.4960 ;
    END
  END w_mask_in[96]
  PIN w_mask_in[97]
    DIRECTION INPUT ;
    USE SIGNAL ;
    PORT
      LAYER M4 ;
        RECT 0 23.5440 0.9600 23.5920 ;
    END
  END w_mask_in[97]
  PIN w_mask_in[98]
    DIRECTION INPUT ;
    USE SIGNAL ;
    PORT
      LAYER M4 ;
        RECT 0 23.6400 0.9600 23.6880 ;
    END
  END w_mask_in[98]
  PIN w_mask_in[99]
    DIRECTION INPUT ;
    USE SIGNAL ;
    PORT
      LAYER M4 ;
        RECT 0 23.7360 0.9600 23.7840 ;
    END
  END w_mask_in[99]
  PIN w_mask_in[100]
    DIRECTION INPUT ;
    USE SIGNAL ;
    PORT
      LAYER M4 ;
        RECT 0 23.8320 0.9600 23.8800 ;
    END
  END w_mask_in[100]
  PIN w_mask_in[101]
    DIRECTION INPUT ;
    USE SIGNAL ;
    PORT
      LAYER M4 ;
        RECT 0 23.9280 0.9600 23.9760 ;
    END
  END w_mask_in[101]
  PIN w_mask_in[102]
    DIRECTION INPUT ;
    USE SIGNAL ;
    PORT
      LAYER M4 ;
        RECT 0 24.0240 0.9600 24.0720 ;
    END
  END w_mask_in[102]
  PIN w_mask_in[103]
    DIRECTION INPUT ;
    USE SIGNAL ;
    PORT
      LAYER M4 ;
        RECT 0 24.1200 0.9600 24.1680 ;
    END
  END w_mask_in[103]
  PIN w_mask_in[104]
    DIRECTION INPUT ;
    USE SIGNAL ;
    PORT
      LAYER M4 ;
        RECT 0 24.2160 0.9600 24.2640 ;
    END
  END w_mask_in[104]
  PIN w_mask_in[105]
    DIRECTION INPUT ;
    USE SIGNAL ;
    PORT
      LAYER M4 ;
        RECT 0 24.3120 0.9600 24.3600 ;
    END
  END w_mask_in[105]
  PIN w_mask_in[106]
    DIRECTION INPUT ;
    USE SIGNAL ;
    PORT
      LAYER M4 ;
        RECT 0 24.4080 0.9600 24.4560 ;
    END
  END w_mask_in[106]
  PIN w_mask_in[107]
    DIRECTION INPUT ;
    USE SIGNAL ;
    PORT
      LAYER M4 ;
        RECT 0 24.5040 0.9600 24.5520 ;
    END
  END w_mask_in[107]
  PIN w_mask_in[108]
    DIRECTION INPUT ;
    USE SIGNAL ;
    PORT
      LAYER M4 ;
        RECT 0 24.6000 0.9600 24.6480 ;
    END
  END w_mask_in[108]
  PIN w_mask_in[109]
    DIRECTION INPUT ;
    USE SIGNAL ;
    PORT
      LAYER M4 ;
        RECT 0 24.6960 0.9600 24.7440 ;
    END
  END w_mask_in[109]
  PIN w_mask_in[110]
    DIRECTION INPUT ;
    USE SIGNAL ;
    PORT
      LAYER M4 ;
        RECT 0 24.7920 0.9600 24.8400 ;
    END
  END w_mask_in[110]
  PIN w_mask_in[111]
    DIRECTION INPUT ;
    USE SIGNAL ;
    PORT
      LAYER M4 ;
        RECT 0 24.8880 0.9600 24.9360 ;
    END
  END w_mask_in[111]
  PIN w_mask_in[112]
    DIRECTION INPUT ;
    USE SIGNAL ;
    PORT
      LAYER M4 ;
        RECT 0 24.9840 0.9600 25.0320 ;
    END
  END w_mask_in[112]
  PIN w_mask_in[113]
    DIRECTION INPUT ;
    USE SIGNAL ;
    PORT
      LAYER M4 ;
        RECT 0 25.0800 0.9600 25.1280 ;
    END
  END w_mask_in[113]
  PIN w_mask_in[114]
    DIRECTION INPUT ;
    USE SIGNAL ;
    PORT
      LAYER M4 ;
        RECT 0 25.1760 0.9600 25.2240 ;
    END
  END w_mask_in[114]
  PIN w_mask_in[115]
    DIRECTION INPUT ;
    USE SIGNAL ;
    PORT
      LAYER M4 ;
        RECT 0 25.2720 0.9600 25.3200 ;
    END
  END w_mask_in[115]
  PIN w_mask_in[116]
    DIRECTION INPUT ;
    USE SIGNAL ;
    PORT
      LAYER M4 ;
        RECT 0 25.3680 0.9600 25.4160 ;
    END
  END w_mask_in[116]
  PIN w_mask_in[117]
    DIRECTION INPUT ;
    USE SIGNAL ;
    PORT
      LAYER M4 ;
        RECT 0 25.4640 0.9600 25.5120 ;
    END
  END w_mask_in[117]
  PIN w_mask_in[118]
    DIRECTION INPUT ;
    USE SIGNAL ;
    PORT
      LAYER M4 ;
        RECT 0 25.5600 0.9600 25.6080 ;
    END
  END w_mask_in[118]
  PIN w_mask_in[119]
    DIRECTION INPUT ;
    USE SIGNAL ;
    PORT
      LAYER M4 ;
        RECT 0 25.6560 0.9600 25.7040 ;
    END
  END w_mask_in[119]
  PIN w_mask_in[120]
    DIRECTION INPUT ;
    USE SIGNAL ;
    PORT
      LAYER M4 ;
        RECT 0 25.7520 0.9600 25.8000 ;
    END
  END w_mask_in[120]
  PIN w_mask_in[121]
    DIRECTION INPUT ;
    USE SIGNAL ;
    PORT
      LAYER M4 ;
        RECT 0 25.8480 0.9600 25.8960 ;
    END
  END w_mask_in[121]
  PIN w_mask_in[122]
    DIRECTION INPUT ;
    USE SIGNAL ;
    PORT
      LAYER M4 ;
        RECT 0 25.9440 0.9600 25.9920 ;
    END
  END w_mask_in[122]
  PIN w_mask_in[123]
    DIRECTION INPUT ;
    USE SIGNAL ;
    PORT
      LAYER M4 ;
        RECT 0 26.0400 0.9600 26.0880 ;
    END
  END w_mask_in[123]
  PIN rd_out[0]
    DIRECTION OUTPUT ;
    USE SIGNAL ;
    PORT
      LAYER M4 ;
        RECT 0 26.1360 0.9600 26.1840 ;
    END
  END rd_out[0]
  PIN rd_out[1]
    DIRECTION OUTPUT ;
    USE SIGNAL ;
    PORT
      LAYER M4 ;
        RECT 0 26.2320 0.9600 26.2800 ;
    END
  END rd_out[1]
  PIN rd_out[2]
    DIRECTION OUTPUT ;
    USE SIGNAL ;
    PORT
      LAYER M4 ;
        RECT 0 26.3280 0.9600 26.3760 ;
    END
  END rd_out[2]
  PIN rd_out[3]
    DIRECTION OUTPUT ;
    USE SIGNAL ;
    PORT
      LAYER M4 ;
        RECT 0 26.4240 0.9600 26.4720 ;
    END
  END rd_out[3]
  PIN rd_out[4]
    DIRECTION OUTPUT ;
    USE SIGNAL ;
    PORT
      LAYER M4 ;
        RECT 0 26.5200 0.9600 26.5680 ;
    END
  END rd_out[4]
  PIN rd_out[5]
    DIRECTION OUTPUT ;
    USE SIGNAL ;
    PORT
      LAYER M4 ;
        RECT 0 26.6160 0.9600 26.6640 ;
    END
  END rd_out[5]
  PIN rd_out[6]
    DIRECTION OUTPUT ;
    USE SIGNAL ;
    PORT
      LAYER M4 ;
        RECT 0 26.7120 0.9600 26.7600 ;
    END
  END rd_out[6]
  PIN rd_out[7]
    DIRECTION OUTPUT ;
    USE SIGNAL ;
    PORT
      LAYER M4 ;
        RECT 0 26.8080 0.9600 26.8560 ;
    END
  END rd_out[7]
  PIN rd_out[8]
    DIRECTION OUTPUT ;
    USE SIGNAL ;
    PORT
      LAYER M4 ;
        RECT 0 26.9040 0.9600 26.9520 ;
    END
  END rd_out[8]
  PIN rd_out[9]
    DIRECTION OUTPUT ;
    USE SIGNAL ;
    PORT
      LAYER M4 ;
        RECT 0 27.0000 0.9600 27.0480 ;
    END
  END rd_out[9]
  PIN rd_out[10]
    DIRECTION OUTPUT ;
    USE SIGNAL ;
    PORT
      LAYER M4 ;
        RECT 0 27.0960 0.9600 27.1440 ;
    END
  END rd_out[10]
  PIN rd_out[11]
    DIRECTION OUTPUT ;
    USE SIGNAL ;
    PORT
      LAYER M4 ;
        RECT 0 27.1920 0.9600 27.2400 ;
    END
  END rd_out[11]
  PIN rd_out[12]
    DIRECTION OUTPUT ;
    USE SIGNAL ;
    PORT
      LAYER M4 ;
        RECT 0 27.2880 0.9600 27.3360 ;
    END
  END rd_out[12]
  PIN rd_out[13]
    DIRECTION OUTPUT ;
    USE SIGNAL ;
    PORT
      LAYER M4 ;
        RECT 0 27.3840 0.9600 27.4320 ;
    END
  END rd_out[13]
  PIN rd_out[14]
    DIRECTION OUTPUT ;
    USE SIGNAL ;
    PORT
      LAYER M4 ;
        RECT 0 27.4800 0.9600 27.5280 ;
    END
  END rd_out[14]
  PIN rd_out[15]
    DIRECTION OUTPUT ;
    USE SIGNAL ;
    PORT
      LAYER M4 ;
        RECT 0 27.5760 0.9600 27.6240 ;
    END
  END rd_out[15]
  PIN rd_out[16]
    DIRECTION OUTPUT ;
    USE SIGNAL ;
    PORT
      LAYER M4 ;
        RECT 0 27.6720 0.9600 27.7200 ;
    END
  END rd_out[16]
  PIN rd_out[17]
    DIRECTION OUTPUT ;
    USE SIGNAL ;
    PORT
      LAYER M4 ;
        RECT 0 27.7680 0.9600 27.8160 ;
    END
  END rd_out[17]
  PIN rd_out[18]
    DIRECTION OUTPUT ;
    USE SIGNAL ;
    PORT
      LAYER M4 ;
        RECT 0 27.8640 0.9600 27.9120 ;
    END
  END rd_out[18]
  PIN rd_out[19]
    DIRECTION OUTPUT ;
    USE SIGNAL ;
    PORT
      LAYER M4 ;
        RECT 0 27.9600 0.9600 28.0080 ;
    END
  END rd_out[19]
  PIN rd_out[20]
    DIRECTION OUTPUT ;
    USE SIGNAL ;
    PORT
      LAYER M4 ;
        RECT 0 28.0560 0.9600 28.1040 ;
    END
  END rd_out[20]
  PIN rd_out[21]
    DIRECTION OUTPUT ;
    USE SIGNAL ;
    PORT
      LAYER M4 ;
        RECT 0 28.1520 0.9600 28.2000 ;
    END
  END rd_out[21]
  PIN rd_out[22]
    DIRECTION OUTPUT ;
    USE SIGNAL ;
    PORT
      LAYER M4 ;
        RECT 0 28.2480 0.9600 28.2960 ;
    END
  END rd_out[22]
  PIN rd_out[23]
    DIRECTION OUTPUT ;
    USE SIGNAL ;
    PORT
      LAYER M4 ;
        RECT 0 28.3440 0.9600 28.3920 ;
    END
  END rd_out[23]
  PIN rd_out[24]
    DIRECTION OUTPUT ;
    USE SIGNAL ;
    PORT
      LAYER M4 ;
        RECT 0 28.4400 0.9600 28.4880 ;
    END
  END rd_out[24]
  PIN rd_out[25]
    DIRECTION OUTPUT ;
    USE SIGNAL ;
    PORT
      LAYER M4 ;
        RECT 0 28.5360 0.9600 28.5840 ;
    END
  END rd_out[25]
  PIN rd_out[26]
    DIRECTION OUTPUT ;
    USE SIGNAL ;
    PORT
      LAYER M4 ;
        RECT 0 28.6320 0.9600 28.6800 ;
    END
  END rd_out[26]
  PIN rd_out[27]
    DIRECTION OUTPUT ;
    USE SIGNAL ;
    PORT
      LAYER M4 ;
        RECT 0 28.7280 0.9600 28.7760 ;
    END
  END rd_out[27]
  PIN rd_out[28]
    DIRECTION OUTPUT ;
    USE SIGNAL ;
    PORT
      LAYER M4 ;
        RECT 0 28.8240 0.9600 28.8720 ;
    END
  END rd_out[28]
  PIN rd_out[29]
    DIRECTION OUTPUT ;
    USE SIGNAL ;
    PORT
      LAYER M4 ;
        RECT 0 28.9200 0.9600 28.9680 ;
    END
  END rd_out[29]
  PIN rd_out[30]
    DIRECTION OUTPUT ;
    USE SIGNAL ;
    PORT
      LAYER M4 ;
        RECT 0 29.0160 0.9600 29.0640 ;
    END
  END rd_out[30]
  PIN rd_out[31]
    DIRECTION OUTPUT ;
    USE SIGNAL ;
    PORT
      LAYER M4 ;
        RECT 0 29.1120 0.9600 29.1600 ;
    END
  END rd_out[31]
  PIN rd_out[32]
    DIRECTION OUTPUT ;
    USE SIGNAL ;
    PORT
      LAYER M4 ;
        RECT 0 29.2080 0.9600 29.2560 ;
    END
  END rd_out[32]
  PIN rd_out[33]
    DIRECTION OUTPUT ;
    USE SIGNAL ;
    PORT
      LAYER M4 ;
        RECT 0 29.3040 0.9600 29.3520 ;
    END
  END rd_out[33]
  PIN rd_out[34]
    DIRECTION OUTPUT ;
    USE SIGNAL ;
    PORT
      LAYER M4 ;
        RECT 0 29.4000 0.9600 29.4480 ;
    END
  END rd_out[34]
  PIN rd_out[35]
    DIRECTION OUTPUT ;
    USE SIGNAL ;
    PORT
      LAYER M4 ;
        RECT 0 29.4960 0.9600 29.5440 ;
    END
  END rd_out[35]
  PIN rd_out[36]
    DIRECTION OUTPUT ;
    USE SIGNAL ;
    PORT
      LAYER M4 ;
        RECT 0 29.5920 0.9600 29.6400 ;
    END
  END rd_out[36]
  PIN rd_out[37]
    DIRECTION OUTPUT ;
    USE SIGNAL ;
    PORT
      LAYER M4 ;
        RECT 0 29.6880 0.9600 29.7360 ;
    END
  END rd_out[37]
  PIN rd_out[38]
    DIRECTION OUTPUT ;
    USE SIGNAL ;
    PORT
      LAYER M4 ;
        RECT 0 29.7840 0.9600 29.8320 ;
    END
  END rd_out[38]
  PIN rd_out[39]
    DIRECTION OUTPUT ;
    USE SIGNAL ;
    PORT
      LAYER M4 ;
        RECT 0 29.8800 0.9600 29.9280 ;
    END
  END rd_out[39]
  PIN rd_out[40]
    DIRECTION OUTPUT ;
    USE SIGNAL ;
    PORT
      LAYER M4 ;
        RECT 0 29.9760 0.9600 30.0240 ;
    END
  END rd_out[40]
  PIN rd_out[41]
    DIRECTION OUTPUT ;
    USE SIGNAL ;
    PORT
      LAYER M4 ;
        RECT 0 30.0720 0.9600 30.1200 ;
    END
  END rd_out[41]
  PIN rd_out[42]
    DIRECTION OUTPUT ;
    USE SIGNAL ;
    PORT
      LAYER M4 ;
        RECT 0 30.1680 0.9600 30.2160 ;
    END
  END rd_out[42]
  PIN rd_out[43]
    DIRECTION OUTPUT ;
    USE SIGNAL ;
    PORT
      LAYER M4 ;
        RECT 0 30.2640 0.9600 30.3120 ;
    END
  END rd_out[43]
  PIN rd_out[44]
    DIRECTION OUTPUT ;
    USE SIGNAL ;
    PORT
      LAYER M4 ;
        RECT 0 30.3600 0.9600 30.4080 ;
    END
  END rd_out[44]
  PIN rd_out[45]
    DIRECTION OUTPUT ;
    USE SIGNAL ;
    PORT
      LAYER M4 ;
        RECT 0 30.4560 0.9600 30.5040 ;
    END
  END rd_out[45]
  PIN rd_out[46]
    DIRECTION OUTPUT ;
    USE SIGNAL ;
    PORT
      LAYER M4 ;
        RECT 0 30.5520 0.9600 30.6000 ;
    END
  END rd_out[46]
  PIN rd_out[47]
    DIRECTION OUTPUT ;
    USE SIGNAL ;
    PORT
      LAYER M4 ;
        RECT 0 30.6480 0.9600 30.6960 ;
    END
  END rd_out[47]
  PIN rd_out[48]
    DIRECTION OUTPUT ;
    USE SIGNAL ;
    PORT
      LAYER M4 ;
        RECT 0 30.7440 0.9600 30.7920 ;
    END
  END rd_out[48]
  PIN rd_out[49]
    DIRECTION OUTPUT ;
    USE SIGNAL ;
    PORT
      LAYER M4 ;
        RECT 0 30.8400 0.9600 30.8880 ;
    END
  END rd_out[49]
  PIN rd_out[50]
    DIRECTION OUTPUT ;
    USE SIGNAL ;
    PORT
      LAYER M4 ;
        RECT 0 30.9360 0.9600 30.9840 ;
    END
  END rd_out[50]
  PIN rd_out[51]
    DIRECTION OUTPUT ;
    USE SIGNAL ;
    PORT
      LAYER M4 ;
        RECT 0 31.0320 0.9600 31.0800 ;
    END
  END rd_out[51]
  PIN rd_out[52]
    DIRECTION OUTPUT ;
    USE SIGNAL ;
    PORT
      LAYER M4 ;
        RECT 0 31.1280 0.9600 31.1760 ;
    END
  END rd_out[52]
  PIN rd_out[53]
    DIRECTION OUTPUT ;
    USE SIGNAL ;
    PORT
      LAYER M4 ;
        RECT 0 31.2240 0.9600 31.2720 ;
    END
  END rd_out[53]
  PIN rd_out[54]
    DIRECTION OUTPUT ;
    USE SIGNAL ;
    PORT
      LAYER M4 ;
        RECT 0 31.3200 0.9600 31.3680 ;
    END
  END rd_out[54]
  PIN rd_out[55]
    DIRECTION OUTPUT ;
    USE SIGNAL ;
    PORT
      LAYER M4 ;
        RECT 0 31.4160 0.9600 31.4640 ;
    END
  END rd_out[55]
  PIN rd_out[56]
    DIRECTION OUTPUT ;
    USE SIGNAL ;
    PORT
      LAYER M4 ;
        RECT 0 31.5120 0.9600 31.5600 ;
    END
  END rd_out[56]
  PIN rd_out[57]
    DIRECTION OUTPUT ;
    USE SIGNAL ;
    PORT
      LAYER M4 ;
        RECT 0 31.6080 0.9600 31.6560 ;
    END
  END rd_out[57]
  PIN rd_out[58]
    DIRECTION OUTPUT ;
    USE SIGNAL ;
    PORT
      LAYER M4 ;
        RECT 0 31.7040 0.9600 31.7520 ;
    END
  END rd_out[58]
  PIN rd_out[59]
    DIRECTION OUTPUT ;
    USE SIGNAL ;
    PORT
      LAYER M4 ;
        RECT 0 31.8000 0.9600 31.8480 ;
    END
  END rd_out[59]
  PIN rd_out[60]
    DIRECTION OUTPUT ;
    USE SIGNAL ;
    PORT
      LAYER M4 ;
        RECT 0 31.8960 0.9600 31.9440 ;
    END
  END rd_out[60]
  PIN rd_out[61]
    DIRECTION OUTPUT ;
    USE SIGNAL ;
    PORT
      LAYER M4 ;
        RECT 0 31.9920 0.9600 32.0400 ;
    END
  END rd_out[61]
  PIN rd_out[62]
    DIRECTION OUTPUT ;
    USE SIGNAL ;
    PORT
      LAYER M4 ;
        RECT 0 32.0880 0.9600 32.1360 ;
    END
  END rd_out[62]
  PIN rd_out[63]
    DIRECTION OUTPUT ;
    USE SIGNAL ;
    PORT
      LAYER M4 ;
        RECT 0 32.1840 0.9600 32.2320 ;
    END
  END rd_out[63]
  PIN rd_out[64]
    DIRECTION OUTPUT ;
    USE SIGNAL ;
    PORT
      LAYER M4 ;
        RECT 0 32.2800 0.9600 32.3280 ;
    END
  END rd_out[64]
  PIN rd_out[65]
    DIRECTION OUTPUT ;
    USE SIGNAL ;
    PORT
      LAYER M4 ;
        RECT 0 32.3760 0.9600 32.4240 ;
    END
  END rd_out[65]
  PIN rd_out[66]
    DIRECTION OUTPUT ;
    USE SIGNAL ;
    PORT
      LAYER M4 ;
        RECT 0 32.4720 0.9600 32.5200 ;
    END
  END rd_out[66]
  PIN rd_out[67]
    DIRECTION OUTPUT ;
    USE SIGNAL ;
    PORT
      LAYER M4 ;
        RECT 0 32.5680 0.9600 32.6160 ;
    END
  END rd_out[67]
  PIN rd_out[68]
    DIRECTION OUTPUT ;
    USE SIGNAL ;
    PORT
      LAYER M4 ;
        RECT 0 32.6640 0.9600 32.7120 ;
    END
  END rd_out[68]
  PIN rd_out[69]
    DIRECTION OUTPUT ;
    USE SIGNAL ;
    PORT
      LAYER M4 ;
        RECT 0 32.7600 0.9600 32.8080 ;
    END
  END rd_out[69]
  PIN rd_out[70]
    DIRECTION OUTPUT ;
    USE SIGNAL ;
    PORT
      LAYER M4 ;
        RECT 0 32.8560 0.9600 32.9040 ;
    END
  END rd_out[70]
  PIN rd_out[71]
    DIRECTION OUTPUT ;
    USE SIGNAL ;
    PORT
      LAYER M4 ;
        RECT 0 32.9520 0.9600 33.0000 ;
    END
  END rd_out[71]
  PIN rd_out[72]
    DIRECTION OUTPUT ;
    USE SIGNAL ;
    PORT
      LAYER M4 ;
        RECT 0 33.0480 0.9600 33.0960 ;
    END
  END rd_out[72]
  PIN rd_out[73]
    DIRECTION OUTPUT ;
    USE SIGNAL ;
    PORT
      LAYER M4 ;
        RECT 0 33.1440 0.9600 33.1920 ;
    END
  END rd_out[73]
  PIN rd_out[74]
    DIRECTION OUTPUT ;
    USE SIGNAL ;
    PORT
      LAYER M4 ;
        RECT 0 33.2400 0.9600 33.2880 ;
    END
  END rd_out[74]
  PIN rd_out[75]
    DIRECTION OUTPUT ;
    USE SIGNAL ;
    PORT
      LAYER M4 ;
        RECT 0 33.3360 0.9600 33.3840 ;
    END
  END rd_out[75]
  PIN rd_out[76]
    DIRECTION OUTPUT ;
    USE SIGNAL ;
    PORT
      LAYER M4 ;
        RECT 0 33.4320 0.9600 33.4800 ;
    END
  END rd_out[76]
  PIN rd_out[77]
    DIRECTION OUTPUT ;
    USE SIGNAL ;
    PORT
      LAYER M4 ;
        RECT 0 33.5280 0.9600 33.5760 ;
    END
  END rd_out[77]
  PIN rd_out[78]
    DIRECTION OUTPUT ;
    USE SIGNAL ;
    PORT
      LAYER M4 ;
        RECT 0 33.6240 0.9600 33.6720 ;
    END
  END rd_out[78]
  PIN rd_out[79]
    DIRECTION OUTPUT ;
    USE SIGNAL ;
    PORT
      LAYER M4 ;
        RECT 0 33.7200 0.9600 33.7680 ;
    END
  END rd_out[79]
  PIN rd_out[80]
    DIRECTION OUTPUT ;
    USE SIGNAL ;
    PORT
      LAYER M4 ;
        RECT 0 33.8160 0.9600 33.8640 ;
    END
  END rd_out[80]
  PIN rd_out[81]
    DIRECTION OUTPUT ;
    USE SIGNAL ;
    PORT
      LAYER M4 ;
        RECT 0 33.9120 0.9600 33.9600 ;
    END
  END rd_out[81]
  PIN rd_out[82]
    DIRECTION OUTPUT ;
    USE SIGNAL ;
    PORT
      LAYER M4 ;
        RECT 0 34.0080 0.9600 34.0560 ;
    END
  END rd_out[82]
  PIN rd_out[83]
    DIRECTION OUTPUT ;
    USE SIGNAL ;
    PORT
      LAYER M4 ;
        RECT 0 34.1040 0.9600 34.1520 ;
    END
  END rd_out[83]
  PIN rd_out[84]
    DIRECTION OUTPUT ;
    USE SIGNAL ;
    PORT
      LAYER M4 ;
        RECT 0 34.2000 0.9600 34.2480 ;
    END
  END rd_out[84]
  PIN rd_out[85]
    DIRECTION OUTPUT ;
    USE SIGNAL ;
    PORT
      LAYER M4 ;
        RECT 0 34.2960 0.9600 34.3440 ;
    END
  END rd_out[85]
  PIN rd_out[86]
    DIRECTION OUTPUT ;
    USE SIGNAL ;
    PORT
      LAYER M4 ;
        RECT 0 34.3920 0.9600 34.4400 ;
    END
  END rd_out[86]
  PIN rd_out[87]
    DIRECTION OUTPUT ;
    USE SIGNAL ;
    PORT
      LAYER M4 ;
        RECT 0 34.4880 0.9600 34.5360 ;
    END
  END rd_out[87]
  PIN rd_out[88]
    DIRECTION OUTPUT ;
    USE SIGNAL ;
    PORT
      LAYER M4 ;
        RECT 0 34.5840 0.9600 34.6320 ;
    END
  END rd_out[88]
  PIN rd_out[89]
    DIRECTION OUTPUT ;
    USE SIGNAL ;
    PORT
      LAYER M4 ;
        RECT 0 34.6800 0.9600 34.7280 ;
    END
  END rd_out[89]
  PIN rd_out[90]
    DIRECTION OUTPUT ;
    USE SIGNAL ;
    PORT
      LAYER M4 ;
        RECT 0 34.7760 0.9600 34.8240 ;
    END
  END rd_out[90]
  PIN rd_out[91]
    DIRECTION OUTPUT ;
    USE SIGNAL ;
    PORT
      LAYER M4 ;
        RECT 0 34.8720 0.9600 34.9200 ;
    END
  END rd_out[91]
  PIN rd_out[92]
    DIRECTION OUTPUT ;
    USE SIGNAL ;
    PORT
      LAYER M4 ;
        RECT 0 34.9680 0.9600 35.0160 ;
    END
  END rd_out[92]
  PIN rd_out[93]
    DIRECTION OUTPUT ;
    USE SIGNAL ;
    PORT
      LAYER M4 ;
        RECT 0 35.0640 0.9600 35.1120 ;
    END
  END rd_out[93]
  PIN rd_out[94]
    DIRECTION OUTPUT ;
    USE SIGNAL ;
    PORT
      LAYER M4 ;
        RECT 0 35.1600 0.9600 35.2080 ;
    END
  END rd_out[94]
  PIN rd_out[95]
    DIRECTION OUTPUT ;
    USE SIGNAL ;
    PORT
      LAYER M4 ;
        RECT 0 35.2560 0.9600 35.3040 ;
    END
  END rd_out[95]
  PIN rd_out[96]
    DIRECTION OUTPUT ;
    USE SIGNAL ;
    PORT
      LAYER M4 ;
        RECT 0 35.3520 0.9600 35.4000 ;
    END
  END rd_out[96]
  PIN rd_out[97]
    DIRECTION OUTPUT ;
    USE SIGNAL ;
    PORT
      LAYER M4 ;
        RECT 0 35.4480 0.9600 35.4960 ;
    END
  END rd_out[97]
  PIN rd_out[98]
    DIRECTION OUTPUT ;
    USE SIGNAL ;
    PORT
      LAYER M4 ;
        RECT 0 35.5440 0.9600 35.5920 ;
    END
  END rd_out[98]
  PIN rd_out[99]
    DIRECTION OUTPUT ;
    USE SIGNAL ;
    PORT
      LAYER M4 ;
        RECT 0 35.6400 0.9600 35.6880 ;
    END
  END rd_out[99]
  PIN rd_out[100]
    DIRECTION OUTPUT ;
    USE SIGNAL ;
    PORT
      LAYER M4 ;
        RECT 0 35.7360 0.9600 35.7840 ;
    END
  END rd_out[100]
  PIN rd_out[101]
    DIRECTION OUTPUT ;
    USE SIGNAL ;
    PORT
      LAYER M4 ;
        RECT 0 35.8320 0.9600 35.8800 ;
    END
  END rd_out[101]
  PIN rd_out[102]
    DIRECTION OUTPUT ;
    USE SIGNAL ;
    PORT
      LAYER M4 ;
        RECT 0 35.9280 0.9600 35.9760 ;
    END
  END rd_out[102]
  PIN rd_out[103]
    DIRECTION OUTPUT ;
    USE SIGNAL ;
    PORT
      LAYER M4 ;
        RECT 0 36.0240 0.9600 36.0720 ;
    END
  END rd_out[103]
  PIN rd_out[104]
    DIRECTION OUTPUT ;
    USE SIGNAL ;
    PORT
      LAYER M4 ;
        RECT 0 36.1200 0.9600 36.1680 ;
    END
  END rd_out[104]
  PIN rd_out[105]
    DIRECTION OUTPUT ;
    USE SIGNAL ;
    PORT
      LAYER M4 ;
        RECT 0 36.2160 0.9600 36.2640 ;
    END
  END rd_out[105]
  PIN rd_out[106]
    DIRECTION OUTPUT ;
    USE SIGNAL ;
    PORT
      LAYER M4 ;
        RECT 0 36.3120 0.9600 36.3600 ;
    END
  END rd_out[106]
  PIN rd_out[107]
    DIRECTION OUTPUT ;
    USE SIGNAL ;
    PORT
      LAYER M4 ;
        RECT 0 36.4080 0.9600 36.4560 ;
    END
  END rd_out[107]
  PIN rd_out[108]
    DIRECTION OUTPUT ;
    USE SIGNAL ;
    PORT
      LAYER M4 ;
        RECT 0 36.5040 0.9600 36.5520 ;
    END
  END rd_out[108]
  PIN rd_out[109]
    DIRECTION OUTPUT ;
    USE SIGNAL ;
    PORT
      LAYER M4 ;
        RECT 0 36.6000 0.9600 36.6480 ;
    END
  END rd_out[109]
  PIN rd_out[110]
    DIRECTION OUTPUT ;
    USE SIGNAL ;
    PORT
      LAYER M4 ;
        RECT 0 36.6960 0.9600 36.7440 ;
    END
  END rd_out[110]
  PIN rd_out[111]
    DIRECTION OUTPUT ;
    USE SIGNAL ;
    PORT
      LAYER M4 ;
        RECT 0 36.7920 0.9600 36.8400 ;
    END
  END rd_out[111]
  PIN rd_out[112]
    DIRECTION OUTPUT ;
    USE SIGNAL ;
    PORT
      LAYER M4 ;
        RECT 0 36.8880 0.9600 36.9360 ;
    END
  END rd_out[112]
  PIN rd_out[113]
    DIRECTION OUTPUT ;
    USE SIGNAL ;
    PORT
      LAYER M4 ;
        RECT 0 36.9840 0.9600 37.0320 ;
    END
  END rd_out[113]
  PIN rd_out[114]
    DIRECTION OUTPUT ;
    USE SIGNAL ;
    PORT
      LAYER M4 ;
        RECT 0 37.0800 0.9600 37.1280 ;
    END
  END rd_out[114]
  PIN rd_out[115]
    DIRECTION OUTPUT ;
    USE SIGNAL ;
    PORT
      LAYER M4 ;
        RECT 0 37.1760 0.9600 37.2240 ;
    END
  END rd_out[115]
  PIN rd_out[116]
    DIRECTION OUTPUT ;
    USE SIGNAL ;
    PORT
      LAYER M4 ;
        RECT 0 37.2720 0.9600 37.3200 ;
    END
  END rd_out[116]
  PIN rd_out[117]
    DIRECTION OUTPUT ;
    USE SIGNAL ;
    PORT
      LAYER M4 ;
        RECT 0 37.3680 0.9600 37.4160 ;
    END
  END rd_out[117]
  PIN rd_out[118]
    DIRECTION OUTPUT ;
    USE SIGNAL ;
    PORT
      LAYER M4 ;
        RECT 0 37.4640 0.9600 37.5120 ;
    END
  END rd_out[118]
  PIN rd_out[119]
    DIRECTION OUTPUT ;
    USE SIGNAL ;
    PORT
      LAYER M4 ;
        RECT 0 37.5600 0.9600 37.6080 ;
    END
  END rd_out[119]
  PIN rd_out[120]
    DIRECTION OUTPUT ;
    USE SIGNAL ;
    PORT
      LAYER M4 ;
        RECT 0 37.6560 0.9600 37.7040 ;
    END
  END rd_out[120]
  PIN rd_out[121]
    DIRECTION OUTPUT ;
    USE SIGNAL ;
    PORT
      LAYER M4 ;
        RECT 0 37.7520 0.9600 37.8000 ;
    END
  END rd_out[121]
  PIN rd_out[122]
    DIRECTION OUTPUT ;
    USE SIGNAL ;
    PORT
      LAYER M4 ;
        RECT 0 37.8480 0.9600 37.8960 ;
    END
  END rd_out[122]
  PIN rd_out[123]
    DIRECTION OUTPUT ;
    USE SIGNAL ;
    PORT
      LAYER M4 ;
        RECT 0 37.9440 0.9600 37.9920 ;
    END
  END rd_out[123]
  PIN VDD
    DIRECTION INOUT ;
    USE POWER ;
    PORT
      LAYER M6 ;
        RECT 0 0.9600 17.7760 1.4400 ;
        RECT 0 9.0240 17.7760 9.5040 ;
        RECT 0 17.0880 17.7760 17.5680 ;
        RECT 0 25.1520 17.7760 25.6320 ;
        RECT 0 33.2160 17.7760 33.6960 ;
    END
  END VDD
  PIN VSS
    DIRECTION INOUT ;
    USE GROUND ;
    PORT
      LAYER M6 ;
        RECT 0 4.9920 17.7760 5.4720 ;
        RECT 0 13.0560 17.7760 13.5360 ;
        RECT 0 21.1200 17.7760 21.6000 ;
        RECT 0 29.1840 17.7760 29.6640 ;
        RECT 0 37.2480 17.7760 37.7280 ;
    END
  END VSS
  OBS
    LAYER M0 ;
      RECT 0 0 17.7760 39.3600 ;
    LAYER M1 ;
      RECT 0 0 17.7760 39.3600 ;
    LAYER M2 ;
      RECT 0 0 17.7760 39.3600 ;
    LAYER M3 ;
      RECT 0 0 17.7760 39.3600 ;
    LAYER VIA0 ;
      RECT 0 0 17.7760 39.3600 ;
    LAYER VIA1 ;
      RECT 0 0 17.7760 39.3600 ;
    LAYER VIA2 ;
      RECT 0 0 17.7760 39.3600 ;
    LAYER VIA3 ;
      RECT 0 0 17.7760 39.3600 ;
    LAYER M4 ;
      RECT 1.0560 0 17.7760 39.3600 ;
  END
END fakeram45_64x124

END LIBRARY
